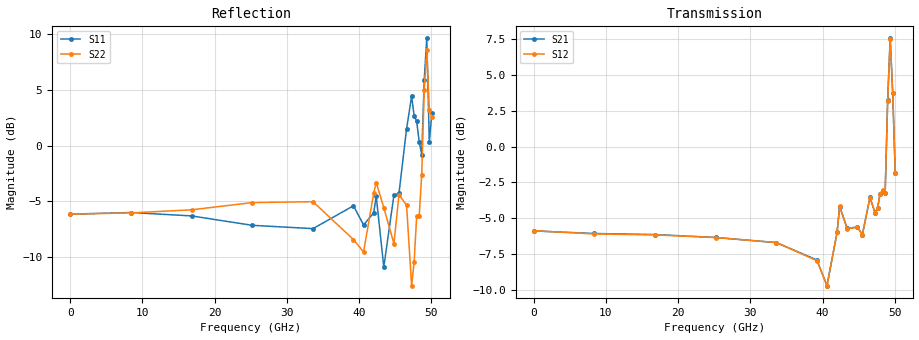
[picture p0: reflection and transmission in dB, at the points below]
! 10/31/2025 3:48:00 PM
! C:\MESURES\046-TRL-DUT-CHEP0603\DUT\DUT-2542B2-CHEP0603F-3-I.S2P
! CHANNEL.1 Sparams
! TR.MEASUREMENT
! CORRECTED.DATA
! RF.CORRECTION: CAL.A: FULL.TWO.PORT.CALCAL.A: Port 1,4
! AVERAGING.OFF
! IF.BANDWIDTH: 500HZ
! SWEEPTYPE:  FREQ.SWEEP(Linear)
! Reference Plane Port Info
! PORT:  PORT1  PORT4
! DISTANCE:  0  m  0  m
! TIME:  0  s  0  s
! PHASE.OFFSET:  0  deg.  0  deg.
! LOSS:  0  dB  0  dB
! REF.LOSS:  0  dB  0  dB
! REF.FREQ:  0  Hz  0  Hz
! Power Info
! POWER:  -10  dBm  -10  dBm
! EFF.POWER:  -10  dBm  -10  dBm
! SOURCE.ATTEN:  0  dB  0  dB
! TEST.ATTEN:  0  dB  0  dB
! PORTZ: Port1:50 Port4:50
# GHZ S RI R 50
! FREQ.GHZ  S11RE  S11IM  S41RE  S41IM  S14RE  S14IM  S44RE  S44IM
!; PortSelection: Port_14 (1-->1,4-->4)
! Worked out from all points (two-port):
!   144 points, 10 MHz to 50.05 GHz, reference 50 ohm
!   highest |S21| = 7.56 dB at 49.35 GHz (marker M1); lowest = -9.7 dB at 40.6 GHz (marker M2)
!   |S21| within 3 dB of the highest: 49.11 GHz to 49.63 GHz (516.4 MHz wide, 1.05 % of centre)
!   lowest |S11| = -10.9 dB at 43.4 GHz (marker M3), VSWR 1.80, Z = 53.8 - j30.7 ohm
!   |S11| at or under -10 dB: 43.31 GHz to 43.76 GHz (444.3 MHz wide, 1.02 % of centre)
!   |S22| runs from -12.6 to 8.5 dB; largest |S21 - S12| = 0.0096
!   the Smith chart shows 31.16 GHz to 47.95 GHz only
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0.01  0.4929 0.0168  0.5068 -0.0179  0.5077 -0.018  0.493 0.0169
8.4088  0.4883 -0.1153  0.486 -0.1029  0.4842 -0.1021  0.4886 -0.1045
16.8076  0.4491 -0.1814  0.4555 -0.1873  0.4547 -0.1857  0.4835 -0.1798
25.2064  0.3811 -0.2189  0.406 -0.2582  0.4062 -0.2572  0.4826 -0.2758
33.6052  0.3128 -0.2875  0.3341 -0.3185  0.3355 -0.3174  0.4381 -0.3502
39.2044  0.4134 -0.344  0.2574 -0.3082  0.2551 -0.3071  0.2517 -0.2841
40.6042  0.4367 0.0632  0.2749 -0.1761  0.276 -0.1751  0.3196 -0.0962
42.004  0.4993 -0.018  0.4348 -0.25  0.435 -0.2513  0.5555 -0.2553
42.35395  0.5718 -0.1609  0.4792 -0.3887  0.4798 -0.3902  0.3816 -0.5672
43.4038  0.1143 -0.2619  0.3213 -0.4055  0.3196 -0.406  0.322 -0.4183
44.8036  0.1909 -0.5688  0.4069 -0.33  0.4059 -0.3272  0.3126 -0.1856
45.5035  0.4944 -0.3584  0.4033 -0.2831  0.4031 -0.2831  0.6004 0.0515
46.55335  0.8432 -0.8385  0.5799 -0.3226  0.5815 -0.3177  0.4514 -0.2991
47.25325  0.9999 -1.331  0.3882 -0.4417  0.3861 -0.4394  0.168 -0.1654
47.6032  0.5131 -1.265  0.3688 -0.4849  0.3704 -0.4821  0.2258 -0.1998
47.95315  0.8834 -0.9344  0.4111 -0.5479  0.4151 -0.5452  0.2278 -0.4256
48.3031  0.6707 -0.798  0.3396 -0.6137  0.3426 -0.6135  0.1103 -0.47
48.65305  0.8377 -0.3604  0.4301 -0.5356  0.4317 -0.5324  0.4196 -0.6112
49.003  1.799 0.8218  -1.022 -1.027  -1.014 -1.03  0.7278 1.623
49.35295  0.9986 2.857  -0.043 -2.386  -0.0448 -2.379  -0.5094 2.626
49.7029  0.8346 -0.6141  -0.1226 1.531  -0.1309 1.527  1.337 -0.5541
50.05285  1.326 -0.451  -0.3828 0.7147  -0.39 0.71  1.337 -0.071
